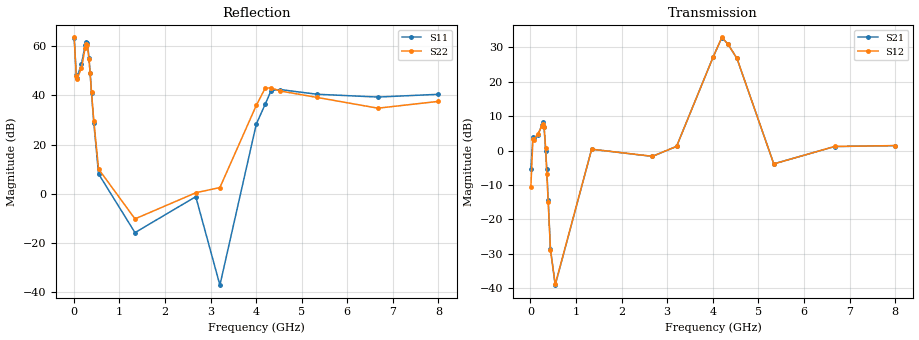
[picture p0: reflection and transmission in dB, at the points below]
!Agilent Technologies,N5230A,US43500312,A.07.50.67
!Agilent N5230A: A.07.50.67
!Date: Tuesday, June 09, 2015 15:41:44
!Correction: S11(Full 2 Port(1,2))
!S21(Full 2 Port(1,2))
!S12(Full 2 Port(1,2))
!S22(Full 2 Port(1,2))
!S2P File: Measurements: S11, S21, S12, S22:
# Hz S  MA  R 50
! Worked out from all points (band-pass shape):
!   1601 points, 10 MHz to 8 GHz, reference 50 ohm
!   highest |S21| = 32.79 dB at 4.2 GHz (marker M1); lowest = -39.0 dB at 544.3 MHz (marker M2)
!   |S21| within 3 dB of the highest: 4.067 GHz to 4.377 GHz (310.1 MHz wide, 7.34 % of centre)
!   lowest |S11| = -37.2 dB at 3.206 GHz (marker M3), VSWR 1.03, Z = 50.7 - j1.2 ohm
!   |S11| at or under -10 dB: 1.039 GHz to 1.906 GHz (866.7 MHz wide, 58.9 % of centre); 2.244 GHz to 2.412 GHz (168.5 MHz wide, 7.24 % of centre); 3.149 GHz to 3.253 GHz (104.2 MHz wide, 3.26 % of centre)
!   |S22| runs from -16.3 to 63.6 dB; largest |S21 - S12| = 0.54
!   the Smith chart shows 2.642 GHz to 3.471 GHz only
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1e7  1487 171.1  0.5444 32.8  0.2983 61.2  1522 -19.4
5.494375e7  257.3 328.3  1.558 9.6  1.463 12.3  248.2 94.1
6.9925e7  230.3 341.9  1.497 -0.3  1.431 2.3  212 96.4
1.698e8  440 418.1  1.685 16.6  1.763 14.2  365.3 136.9
2.497e8  1045 418.2  2.349 13.9  2.273 13.7  913.3 131.3
2.796625e8  1250 433.0  2.592 35.7  2.451 37.3  1123 146.4
2.996375e8  1165 442.8  2.207 45.9  2.187 46.0  1068 157.2
3.345938e8  574.5 478.4  0.9852 88.9  1.083 88.1  549.1 195.3
3.595625e8  285.1 492.6  0.5357 103.8  0.4617 100.4  281.4 212.7
3.89525e8  113.4 499.1  0.1943 114.8  0.1811 113.5  116.5 224.4
4.394625e8  27.92 511.6  0.03745 118.6  0.03641 124.9  30.87 249.4
5.443312e8  2.536 556.4  0.01117 158.5  0.01144 157.7  3.186 335.0
1.343331e9  0.1617 859.4  1.044 201.3  1.045 201.3  0.3078 801.4
2.676662e9  0.8717 729.9  0.8228 199.2  0.8244 199.2  1.047 1249.4
3.206e9  0.01381 661.2  1.148 236.0  1.149 236.0  1.337 1383.7
4.005e9  26.33 630.5  22.43 280.3  22.44 280.6  63.09 1536.4
4.199756e9  66.29 405.8  43.58 196.1  43.75 196.7  140.8 1492.0
4.329594e9  126.1 348.7  35.13 140.9  35.17 141.4  143.1 1462.3
4.529344e9  131.9 307.9  21.72 87.9  21.81 88.2  123.3 1442.3
5.338331e9  106 309.6  0.641 -19.4  0.6392 -19.8  91.26 1422.0
6.671662e9  92.86 322.1  1.142 33.2  1.145 33.0  55.16 1366.8
8e9  105.7 330.9  1.177 20.7  1.18 20.6  75.87 1324.2
